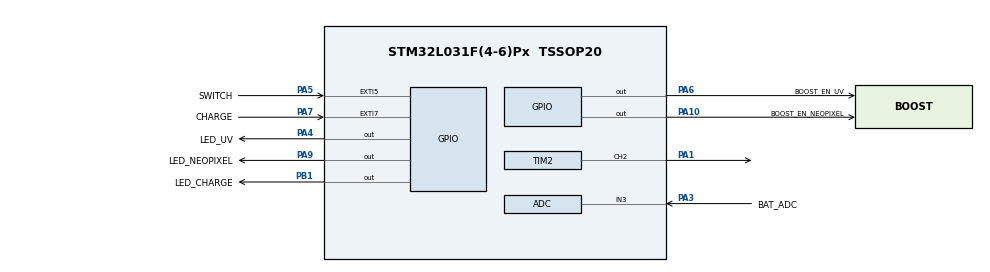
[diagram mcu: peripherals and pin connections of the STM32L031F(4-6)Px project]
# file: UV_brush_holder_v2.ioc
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ADC.ContinuousConvMode=ENABLE
ADC.LowPowerAutoPowerOff=DISABLE
ADC.LowPowerAutoWait=DISABLE
ADC.LowPowerFrequencyMode=DISABLE
Dma.Request0=TIM2_CH2
Dma.TIM2_CH2.0.Direction=DMA_MEMORY_TO_PERIPH
Dma.TIM2_CH2.0.Instance=DMA1_Channel3
Dma.TIM2_CH2.0.MemDataAlignment=DMA_MDATAALIGN_BYTE
Dma.TIM2_CH2.0.MemInc=DMA_MINC_ENABLE
Dma.TIM2_CH2.0.Mode=DMA_CIRCULAR
Dma.TIM2_CH2.0.PeriphDataAlignment=DMA_PDATAALIGN_HALFWORD
Dma.TIM2_CH2.0.PeriphInc=DMA_PINC_DISABLE
Dma.TIM2_CH2.0.Priority=DMA_PRIORITY_LOW
IWDG.Prescaler=IWDG_PRESCALER_128
IWDG.Reload=4095
IWDG.Window=4095
Mcu.Family=STM32L0
Mcu.Name=STM32L031F(4-6)Px
Mcu.Package=TSSOP20
NVIC.DMA1_Channel2_3_IRQn=true\:0\:0\:false\:false\:true\:false\:true
NVIC.EXTI4_15_IRQn=true\:0\:0\:false\:false\:true\:true\:true
NVIC.PVD_IRQn=true\:0\:0\:false\:false\:true\:true\:true
PA1.Signal=S_TIM2_CH2
PA10.GPIO_Label=BOOST_EN_NEOPIXEL
PA10.Signal=GPIO_Output
PA13.Mode=Serial_Wire
PA13.Signal=SYS_SWDIO
PA14.Mode=Serial_Wire
PA14.Signal=SYS_SWCLK
PA3.GPIO_Label=BAT_ADC
PA3.Mode=IN3
PA3.Signal=ADC_IN3
PA4.GPIO_Label=LED_UV
PA4.Signal=GPIO_Output
PA5.GPIO_Label=SWITCH
PA5.GPIO_ModeDefaultEXTI=GPIO_MODE_IT_RISING
PA5.Signal=GPXTI5
PA6.GPIO_Label=BOOST_EN_UV
PA6.Signal=GPIO_Output
PA7.GPIO_Label=CHARGE
PA7.GPIO_ModeDefaultEXTI=GPIO_MODE_IT_RISING
PA7.Signal=GPXTI7
PA9.GPIO_Label=LED_NEOPIXEL
PA9.Signal=GPIO_Output
PB1.GPIO_Label=LED_CHARGE
PB1.Signal=GPIO_Output
ProjectManager.HeapSize=0x200
ProjectManager.StackSize=0x400
ProjectManager.TargetToolchain=STM32CubeIDE
RCC.AHBFreq_Value=32000000
RCC.APB1Freq_Value=32000000
RCC.APB1TimFreq_Value=32000000
RCC.APB2Freq_Value=32000000
RCC.APB2TimFreq_Value=32000000
RCC.HCLKFreq_Value=32000000
RCC.HSE_VALUE=8000000
RCC.HSI16_VALUE=16000000
RCC.HSI_VALUE=16000000
RCC.LSE_VALUE=32768
RCC.MSI_VALUE=2097000
RCC.PLLMUL=RCC_PLLMUL_4
RCC.SYSCLKFreq_VALUE=32000000
RCC.SYSCLKSource=RCC_SYSCLKSOURCE_PLLCLK
RCC.VCOOutputFreq_Value=64000000
SH.S_TIM2_CH2.0=TIM2_CH2,PWM Generation2 CH2
TIM2.AutoReloadPreload=TIM_AUTORELOAD_PRELOAD_ENABLE
TIM2.Channel-PWM\ Generation2\ CH2=TIM_CHANNEL_2
TIM2.Period=39
TIM2.Prescaler=0
VP_IWDG_VS_IWDG.Mode=IWDG_Activate
VP_TIM2_VS_ClockSourceINT.Mode=Internal
board=custom

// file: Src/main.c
/* USER CODE BEGIN Header */
/**
  ******************************************************************************
  * @file           : main.c
  * @brief          : Main program body
  ******************************************************************************
  * @attention
  *
  * <h2><center>&copy; Copyright (c) 2019 STMicroelectronics.
  * All rights reserved.</center></h2>
  *
  * This software component is licensed by ST under BSD 3-Clause license,
  * the "License"; You may not use this file except in compliance with the
  * License. You may obtain a copy of the License at:
  *                        opensource.org/licenses/BSD-3-Clause
  *
  ******************************************************************************
  */
/* USER CODE END Header */

#include "main.h"

/* USER CODE BEGIN Includes */
#include "brush.h"
#include "neopixel.h"

#define BAT_MIN_LIMIT 10
#define BAT_MIN 30
#define BAT_MAX 90

#define BAT_MIN_ADC 3367
#define BAT_MAX_ADC 3895
/* USER CODE END Includes */

ADC_HandleTypeDef hadc;

IWDG_HandleTypeDef hiwdg;

TIM_HandleTypeDef htim2;
DMA_HandleTypeDef hdma_tim2_ch2;
DMA_HandleTypeDef hdma_tim2_ch1;
DMA_HandleTypeDef hdma_tim2_ch3;

/* USER CODE BEGIN PV */

uint8_t isSwitch = 0;
uint8_t isCharging = 0;
uint8_t isLowBat = 0;

uint8_t isRunning = 0;

uint8_t isMoodLighting = 0;
uint8_t isUVLighting = 0;

uint8_t step;

uint8_t clickCount = 0;
uint8_t getCount = 0;
uint8_t pastCount = 0;

uint32_t nowTick = 0;
uint32_t pastTick = 0;

uint32_t nowLedTick = 0;
uint32_t pastLedTick = 0;

uint32_t nowADCTick = 0;
uint32_t pastADCTick = 0;

uint32_t nowBatTick = 0;
uint32_t pastBatTick = 0;

uint32_t nowSleepTick = 0;
uint32_t pastSleepTick = 0;

uint16_t adcValue = 0;
float adc_A = 0;
uint16_t adc_B = 0;

/* USER CODE END PV */

void SystemClock_Config(void);
static void MX_GPIO_Init(void);
static void MX_DMA_Init(void);
static void MX_TIM2_Init(void);
static void MX_ADC_Init(void);
static void MX_IWDG_Init(void);

int main(void)
{

  /* MCU Configuration--------------------------------------------------------*/

  /* Reset of all peripherals, Initializes the Flash interface and the Systick. */
  HAL_Init();

  /* Configure the system clock */
  SystemClock_Config();

  /* Initialize all configured peripherals */
  MX_GPIO_Init();
  MX_DMA_Init();
  MX_TIM2_Init();
  MX_ADC_Init();
  MX_IWDG_Init();
  /* USER CODE BEGIN 2 */

  /*
   * if IWDG?
   * */
  if(__HAL_RCC_GET_FLAG(RCC_FLAG_IWDGRST) == SET)
  {

	  set_charging_led(ON);
	  __HAL_RCC_CLEAR_RESET_FLAGS();
  }
  else
  {
	  set_charging_led(OFF);
  }

  HAL_Delay(1000);

  HAL_ADC_Start(&hadc);

  set_charging_led(OFF);
  set_neopixel_led(OFF);
  set_uv_led(OFF);
  set_neopixel_boost(OFF);
  set_uv_boost(OFF);

  neopixel_begin(1);

  /* USER CODE END 2 */

  /* Infinite loop */
  while (1)
  {

    /* USER CODE BEGIN 3 */

	  HAL_IWDG_Refresh(&hiwdg);
	  isCharging = HAL_GPIO_ReadPin(CHARGE_GPIO_Port, CHARGE_Pin);

	  /*
	   * getAdcValue
	   *
	   * */
	  nowBatTick = HAL_GetTick();
	  if(nowBatTick - pastBatTick > 100)
	  {
//		  HAL_ADC_PollForConversion(&hadc, 0xFFFF);
//		  adcValue = HAL_ADC_GetValue(&hadc);
//		  adc_A = (float)(adcValue - 3368) * 0.1953;
//		  adc_B = adc_A;
//		  pastBatTick = nowBatTick;
	  }
	  if(isCharging)
	  {
		  if(adc_B > BAT_MAX)
			  set_charging_led(OFF);
		  else
			  set_charging_led(ON);

		  isLowBat = 0;
	  }
	  else
	  {
		  if(adc_B < BAT_MIN)
		  {
			  for(uint8_t i = 0; i < 6; i ++)
			  {
				  set_charging_led(TOGGLE);
				  HAL_Delay(500);
			  }
			  isLowBat = 1;
		  }
	  }

	  set_neopixel_boost(ON);
	  set_neopixel_led(ON);
	  nowLedTick = HAL_GetTick();
	  if(nowLedTick > 50)
	  {
		  //add dmad
		  neopixel_SetColor(1, 255, 100, 10, 50);
		  pastLedTick = nowLedTick;
	  }

/*
	  nowTick = HAL_GetTick();
	  if(isSwitch)
	  {
		  if(nowTick - pastTick > 800)
		  {
			  clickCount++;
			  isSwitch = 0;
			  pastTick = nowTick;
		  }
	  }
	  if(nowTick - pastTick > 1000)
	  {
		  getCount = clickCount;
		  if(getCount != pastCount)
		  {
			  step++;
		  }
		  switch(step)
		  {
		  case 1:
			  isRunning = 1;
			  isMoodLighting = 0;
			  isUVLighting = 1;
			  break;
		  case 2:
			  isRunning = 1;
			  isMoodLighting = 1;
			  isUVLighting = 0;
			  break;
		  case 3:
			  isRunning = 0;
			  isMoodLighting = 0;
			  isUVLighting = 0;
			  step = 0;
			  break;
		  default:
			  isRunning = 0;
			  isMoodLighting = 0;
			  isUVLighting = 0;
			  step = 0;
			  break;
		  }
		  isSwitch = 0;
		  pastCount = getCount;
		  pastTick = nowTick;
	  }

	  nowSleepTick = HAL_GetTick();

	  if(nowSleepTick - pastSleepTick > 5000)
	  {
		  if(isLowBat)
		  {
			  //goToSleep;
			  set_charging_led(OFF);
			  set_neopixel_boost(OFF);
			  set_neopixel_led(OFF);
			  set_uv_boost(OFF);
			  set_uv_led(OFF);
			  HAL_SuspendTick();
			  HAL_PWR_EnterSLEEPMode(PWR_LOWPOWERREGULATOR_ON, PWR_SLEEPENTRY_WFI);
			  HAL_ResumeTick();
		  }
		  else
		  {
			  if(isRunning)
			  {
				  //don't sleep;
			  }
			  else
			  {
				  if(isCharging)
				  {
					  //don't sleep;
				  }
				  else
				  {
					  //goToSleep;
					  set_charging_led(OFF);
					  set_neopixel_boost(OFF);
					  set_neopixel_led(OFF);
					  set_uv_boost(OFF);
					  set_uv_led(OFF);
					  HAL_SuspendTick();
					  HAL_PWR_EnterSLEEPMode(PWR_LOWPOWERREGULATOR_ON, PWR_SLEEPENTRY_WFI);
					  HAL_ResumeTick();
				  }
			  }
		  }
		  pastSleepTick = nowSleepTick;
	  }

*/
  }
  /* USER CODE END 3 */
}

void SystemClock_Config(void)
{
  RCC_OscInitTypeDef RCC_OscInitStruct = {0};
  RCC_ClkInitTypeDef RCC_ClkInitStruct = {0};

  /** Configure the main internal regulator output voltage
  */
  __HAL_PWR_VOLTAGESCALING_CONFIG(PWR_REGULATOR_VOLTAGE_SCALE1);
  /** Initializes the CPU, AHB and APB busses clocks
  */
  RCC_OscInitStruct.OscillatorType = RCC_OSCILLATORTYPE_HSI|RCC_OSCILLATORTYPE_LSI;
  RCC_OscInitStruct.HSIState = RCC_HSI_ON;
  RCC_OscInitStruct.HSICalibrationValue = RCC_HSICALIBRATION_DEFAULT;
  RCC_OscInitStruct.LSIState = RCC_LSI_ON;
  RCC_OscInitStruct.PLL.PLLState = RCC_PLL_ON;
  RCC_OscInitStruct.PLL.PLLSource = RCC_PLLSOURCE_HSI;
  RCC_OscInitStruct.PLL.PLLMUL = RCC_PLLMUL_3;
  RCC_OscInitStruct.PLL.PLLDIV = RCC_PLLDIV_3;
  if (HAL_RCC_OscConfig(&RCC_OscInitStruct) != HAL_OK)
  {
    Error_Handler();
  }
  /** Initializes the CPU, AHB and APB busses clocks
  */
  RCC_ClkInitStruct.ClockType = RCC_CLOCKTYPE_HCLK|RCC_CLOCKTYPE_SYSCLK
                              |RCC_CLOCKTYPE_PCLK1|RCC_CLOCKTYPE_PCLK2;
  RCC_ClkInitStruct.SYSCLKSource = RCC_SYSCLKSOURCE_PLLCLK;
  RCC_ClkInitStruct.AHBCLKDivider = RCC_SYSCLK_DIV2;
  RCC_ClkInitStruct.APB1CLKDivider = RCC_HCLK_DIV1;
  RCC_ClkInitStruct.APB2CLKDivider = RCC_HCLK_DIV1;

  if (HAL_RCC_ClockConfig(&RCC_ClkInitStruct, FLASH_LATENCY_0) != HAL_OK)
  {
    Error_Handler();
  }
}

static void MX_ADC_Init(void)
{

  ADC_ChannelConfTypeDef sConfig = {0};

  /** Configure the global features of the ADC (Clock, Resolution, Data Alignment and number of conversion)
  */
  hadc.Instance = ADC1;
  hadc.Init.OversamplingMode = DISABLE;
  hadc.Init.ClockPrescaler = ADC_CLOCK_SYNC_PCLK_DIV2;
  hadc.Init.Resolution = ADC_RESOLUTION_12B;
  hadc.Init.SamplingTime = ADC_SAMPLETIME_1CYCLE_5;
  hadc.Init.ScanConvMode = ADC_SCAN_DIRECTION_FORWARD;
  hadc.Init.DataAlign = ADC_DATAALIGN_RIGHT;
  hadc.Init.ContinuousConvMode = ENABLE;
  hadc.Init.DiscontinuousConvMode = DISABLE;
  hadc.Init.ExternalTrigConvEdge = ADC_EXTERNALTRIGCONVEDGE_NONE;
  hadc.Init.ExternalTrigConv = ADC_SOFTWARE_START;
  hadc.Init.DMAContinuousRequests = DISABLE;
  hadc.Init.EOCSelection = ADC_EOC_SINGLE_CONV;
  hadc.Init.Overrun = ADC_OVR_DATA_PRESERVED;
  hadc.Init.LowPowerAutoWait = DISABLE;
  hadc.Init.LowPowerFrequencyMode = DISABLE;
  hadc.Init.LowPowerAutoPowerOff = DISABLE;
  if (HAL_ADC_Init(&hadc) != HAL_OK)
  {
    Error_Handler();
  }
  /** Configure for the selected ADC regular channel to be converted.
  */
  sConfig.Channel = ADC_CHANNEL_3;
  sConfig.Rank = ADC_RANK_CHANNEL_NUMBER;
  if (HAL_ADC_ConfigChannel(&hadc, &sConfig) != HAL_OK)
  {
    Error_Handler();
  }

}

static void MX_IWDG_Init(void)
{

  hiwdg.Instance = IWDG;
  hiwdg.Init.Prescaler = IWDG_PRESCALER_128;
  hiwdg.Init.Window = 4095;
  hiwdg.Init.Reload = 4095;
  if (HAL_IWDG_Init(&hiwdg) != HAL_OK)
  {
    Error_Handler();
  }

}

static void MX_TIM2_Init(void)
{

  TIM_ClockConfigTypeDef sClockSourceConfig = {0};
  TIM_MasterConfigTypeDef sMasterConfig = {0};
  TIM_OC_InitTypeDef sConfigOC = {0};

  htim2.Instance = TIM2;
  htim2.Init.Prescaler = 0;
  htim2.Init.CounterMode = TIM_COUNTERMODE_UP;
  htim2.Init.Period = 10;
  htim2.Init.ClockDivision = TIM_CLOCKDIVISION_DIV1;
  htim2.Init.AutoReloadPreload = TIM_AUTORELOAD_PRELOAD_ENABLE;
  if (HAL_TIM_Base_Init(&htim2) != HAL_OK)
  {
    Error_Handler();
  }
  sClockSourceConfig.ClockSource = TIM_CLOCKSOURCE_INTERNAL;
  if (HAL_TIM_ConfigClockSource(&htim2, &sClockSourceConfig) != HAL_OK)
  {
    Error_Handler();
  }
  if (HAL_TIM_PWM_Init(&htim2) != HAL_OK)
  {
    Error_Handler();
  }
  sMasterConfig.MasterOutputTrigger = TIM_TRGO_RESET;
  sMasterConfig.MasterSlaveMode = TIM_MASTERSLAVEMODE_DISABLE;
  if (HAL_TIMEx_MasterConfigSynchronization(&htim2, &sMasterConfig) != HAL_OK)
  {
    Error_Handler();
  }
  sConfigOC.OCMode = TIM_OCMODE_PWM1;
  sConfigOC.Pulse = 0;
  sConfigOC.OCPolarity = TIM_OCPOLARITY_HIGH;
  sConfigOC.OCFastMode = TIM_OCFAST_DISABLE;
  if (HAL_TIM_PWM_ConfigChannel(&htim2, &sConfigOC, TIM_CHANNEL_1) != HAL_OK)
  {
    Error_Handler();
  }
  if (HAL_TIM_PWM_ConfigChannel(&htim2, &sConfigOC, TIM_CHANNEL_2) != HAL_OK)
  {
    Error_Handler();
  }
  if (HAL_TIM_PWM_ConfigChannel(&htim2, &sConfigOC, TIM_CHANNEL_3) != HAL_OK)
  {
    Error_Handler();
  }
  HAL_TIM_MspPostInit(&htim2);

}

static void MX_DMA_Init(void)
{
  /* DMA controller clock enable */
  __HAL_RCC_DMA1_CLK_ENABLE();

  /* DMA interrupt init */
  /* DMA1_Channel1_IRQn interrupt configuration */
  HAL_NVIC_SetPriority(DMA1_Channel1_IRQn, 0, 0);
  HAL_NVIC_EnableIRQ(DMA1_Channel1_IRQn);
  /* DMA1_Channel2_3_IRQn interrupt configuration */
  HAL_NVIC_SetPriority(DMA1_Channel2_3_IRQn, 0, 0);
  HAL_NVIC_EnableIRQ(DMA1_Channel2_3_IRQn);
  /* DMA1_Channel4_5_6_7_IRQn interrupt configuration */
  HAL_NVIC_SetPriority(DMA1_Channel4_5_6_7_IRQn, 0, 0);
  HAL_NVIC_EnableIRQ(DMA1_Channel4_5_6_7_IRQn);

}

static void MX_GPIO_Init(void)
{
  GPIO_InitTypeDef GPIO_InitStruct = {0};

  /* GPIO Ports Clock Enable */
  __HAL_RCC_GPIOA_CLK_ENABLE();
  __HAL_RCC_GPIOB_CLK_ENABLE();

  /*Configure GPIO pin Output Level */
  HAL_GPIO_WritePin(GPIOA, LED_UV_Pin|BOOST_EN_UV_Pin|LED_NEOPIXEL_Pin|BOOST_EN_NEOPIXEL_Pin, GPIO_PIN_RESET);

  /*Configure GPIO pin Output Level */
  HAL_GPIO_WritePin(LED_CHARGE_GPIO_Port, LED_CHARGE_Pin, GPIO_PIN_RESET);

  /*Configure GPIO pins : LED_UV_Pin BOOST_EN_UV_Pin LED_NEOPIXEL_Pin BOOST_EN_NEOPIXEL_Pin */
  GPIO_InitStruct.Pin = LED_UV_Pin|BOOST_EN_UV_Pin|LED_NEOPIXEL_Pin|BOOST_EN_NEOPIXEL_Pin;
  GPIO_InitStruct.Mode = GPIO_MODE_OUTPUT_PP;
  GPIO_InitStruct.Pull = GPIO_NOPULL;
  GPIO_InitStruct.Speed = GPIO_SPEED_FREQ_LOW;
  HAL_GPIO_Init(GPIOA, &GPIO_InitStruct);

  /*Configure GPIO pins : SWITCH_Pin CHARGE_Pin */
  GPIO_InitStruct.Pin = SWITCH_Pin|CHARGE_Pin;
  GPIO_InitStruct.Mode = GPIO_MODE_IT_RISING;
  GPIO_InitStruct.Pull = GPIO_NOPULL;
  HAL_GPIO_Init(GPIOA, &GPIO_InitStruct);

  /*Configure GPIO pin : LED_CHARGE_Pin */
  GPIO_InitStruct.Pin = LED_CHARGE_Pin;
  GPIO_InitStruct.Mode = GPIO_MODE_OUTPUT_PP;
  GPIO_InitStruct.Pull = GPIO_NOPULL;
  GPIO_InitStruct.Speed = GPIO_SPEED_FREQ_LOW;
  HAL_GPIO_Init(LED_CHARGE_GPIO_Port, &GPIO_InitStruct);

  /* EXTI interrupt init*/
  HAL_NVIC_SetPriority(EXTI4_15_IRQn, 0, 0);
  HAL_NVIC_EnableIRQ(EXTI4_15_IRQn);

}

/* USER CODE BEGIN 4 */
void HAL_GPIO_EXTI_Callback(uint16_t GPIO_Pin)
{
	if(GPIO_Pin == SWITCH_Pin)
	{
		isSwitch = 1;
	}
	else if(GPIO_Pin == CHARGE_Pin)
	{
		isCharging = 1;
	}
}
/* USER CODE END 4 */

void Error_Handler(void)
{
}

/************************ (C) COPYRIGHT STMicroelectronics *****END OF FILE****/
